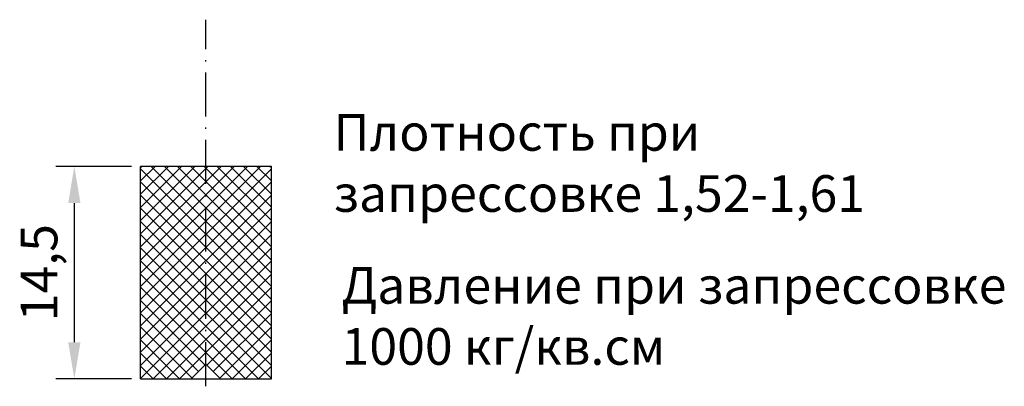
# Model space of a CAD drawing. Units: millimetres. Extents: x -12.7 to 54.4, y -0.5 to 24.5.
import ezdxf

# ---------------------------------------------------------------- set-up
doc = ezdxf.new("R2010")
doc.units = ezdxf.units.MM
doc.linetypes.add('ACAD_ISO10W100', pattern=[18, 12, -3, 0, -3])
doc.dimstyles.new('ISO-25', dxfattribs={"dimtxt": 2.5, "dimasz": 2.5, "dimexe": 1.25, "dimexo": 0.625, "dimtad": 1, "dimtxsty": 'Standard', "dimcen": 2.5, "dimadec": 0, "dimazin": 0, "dimtfac": 1, "dimtmove": 0, "dimatfit": 3, "dimfxl": 0, "dimarcsym": 0})

# ---------------------------------------------------------------- blocks, each defined once
blk = doc.blocks.new('*D5')
at = {"color": 0, "lineweight": -2, "ltscale": 0.25}
for p, q in [((-5.085, 14.5), (-10.222, 14.5)), ((-8.972, 12), (-8.972, 2.5)), ((-5.085, 0), (-10.222, 0))]:
    blk.add_line(p, q, dxfattribs=at)
at = {"color": 0, "lineweight": 15, "ltscale": 0.25}
for points in [[(-9.388, 12), (-8.555, 12), (-8.972, 14.5)], [(-9.388, 2.5), (-8.555, 2.5), (-8.972, 0)]]:
    blk.add_solid(points, dxfattribs=at)
at = {"layer": 'Defpoints', "color": 0, "lineweight": 15, "ltscale": 0.25}
for p in [(-4.46, 14.5), (-8.972, 0), (-4.46, 0)]:
    blk.add_point(p, dxfattribs=at)
at = {"color": 0, "lineweight": 15, "ltscale": 0.25, "insert": (-11.055, 7.25), "char_height": 2.5, "attachment_point": 5, "rotation": 90}
blk.add_mtext('14,5', dxfattribs=at)

msp = doc.modelspace()

# ---------------------------------------------------------------- hatches: boundary and pattern name
at = {"lineweight": 15, "ltscale": 0.25}
h = msp.add_hatch(dxfattribs=at)
h.set_pattern_fill('ANSI37', scale=0.2, angle=90, style=0)
h.paths.add_polyline_path([(0, 14.5), (-4.46, 14.5), (-4.46, 0), (-1, 0), (0, 1)])
h.paths.add_polyline_path([(4.46, 14.5), (0, 14.5), (0, 1), (1, 0), (4.46, 0)])

# ---------------------------------------------------------------- linework, layer by layer
at = {"color": 1, "linetype": 'ACAD_ISO10W100', "lineweight": 25, "ltscale": 0.25}
msp.add_line((0, -0.5), (0, 24.5), dxfattribs=at)
at = {"color": 7, "lineweight": 30, "ltscale": 0.25}
for p, q in [((-4.46, 0), (-4.46, 14.5)), ((4.46, 14.5), (-4.46, 14.5)), ((4.46, 0), (4.46, 14.5)), ((-1, 0), (0, 1)), ((0, 1), (1, 0)), ((-4.46, 0), (4.46, 0))]:
    msp.add_line(p, q, dxfattribs=at)

# ---------------------------------------------------------------- texts
at = {"color": 7, "lineweight": 15, "ltscale": 0.25}
for s, p in [('Плотность при', (8.695, 15.564)), ('запрессовке 1,52-1,61', (8.695, 11.397)), ('Давление при запрессовке', (9.247, 5.136)), ('1000 кг/кв.см', (9.247, 0.969))]:
    msp.add_text(s, height=2.5, dxfattribs=at).set_placement(p)

# ---------------------------------------------------------------- dimensions: what is measured, and where the dimension line sits
dim = msp.add_linear_dim(base=(-8.972, 0), p1=(-4.46, 14.5), p2=(-4.46, 0), angle=90, dimstyle='ISO-25', dxfattribs=at)
dim.commit()
dim.dimension.update_dxf_attribs({"geometry": '*D5', "text_midpoint": (-11.055, 7.25)})

doc.saveas('drawing.dxf')
